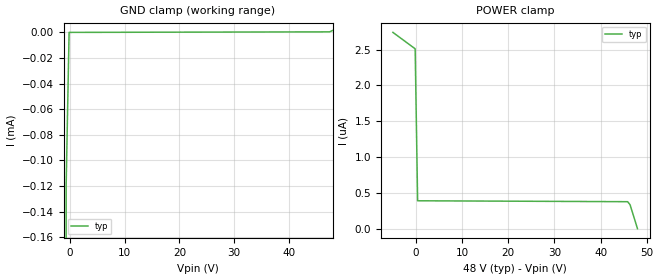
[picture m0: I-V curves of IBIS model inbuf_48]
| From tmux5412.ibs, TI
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| inbuf_48
[Model]   inbuf_48
Model_type   Input
Vinl = 0.8
Vinh = 1.3
|   typ   min   max
C_comp   1.008417e-12   NA   NA
[Voltage Range]   48   NA   NA
[Temperature Range]   27   NA   NA
[Power Clamp Reference]   48   NA   NA
[GND Clamp Reference]   0   NA   NA
[GND Clamp]
|   Voltage   I(typ)   I(min)   I(max)
-5V       -4.814A    NA         NA
-1.253V   -132.2mA   NA         NA
-717.2mV  -119.1uA   NA         NA
-181.8mV  -38.13nA   NA         NA
47.46V    388.8nA    NA         NA
48V       1.431uA    NA         NA
[POWER Clamp]
|   Voltage   I(typ)   I(min)   I(max)
-5V       2.739uA    NA         NA
-181.8mV  2.51uA     NA         NA
353.5mV   388.9nA    NA         NA
45.86V    376.1nA    NA         NA
46.39V    333.7nA    NA         NA
48V       -241.9pA   NA         NA
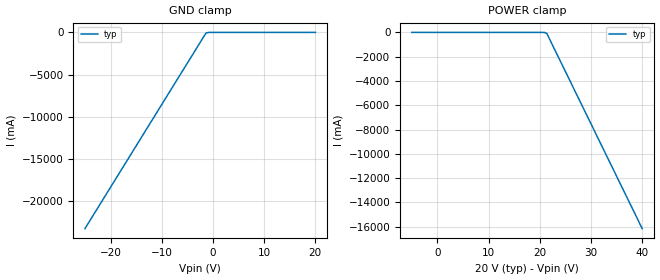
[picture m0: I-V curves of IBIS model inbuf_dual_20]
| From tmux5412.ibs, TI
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| inbuf_dual_20
[Model]   inbuf_dual_20
Model_type   Input
Vinl = 0.8
Vinh = 1.3
|   typ   min   max
C_comp   2.533030e-12   NA   NA
[Voltage Range]   20   NA   NA
[Temperature Range]   27   NA   NA
[Power Clamp Reference]   20   NA   NA
[GND Clamp Reference]   0   NA   NA
[GND Clamp]
|   Voltage   I(typ)   I(min)   I(max)
-25V      -23.23A    NA         NA
-1.364V   -80.68mA   NA         NA
-909.1mV  -7.638mA   NA         NA
-454.5mV  -770.5nA   NA         NA
20V       795.1nA    NA         NA
[POWER Clamp]
|   Voltage   I(typ)   I(min)   I(max)
-5V       1.451uA    NA         NA
20.45V    -770.5nA   NA         NA
20.91V    -7.638mA   NA         NA
21.36V    -80.68mA   NA         NA
40V       -16.16A    NA         NA
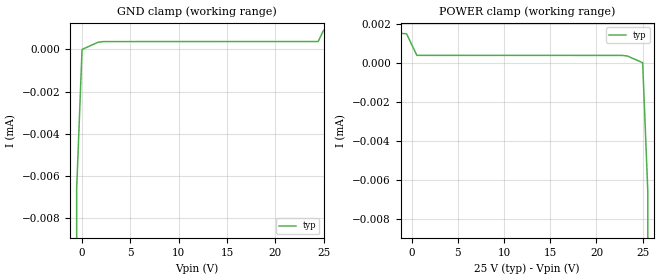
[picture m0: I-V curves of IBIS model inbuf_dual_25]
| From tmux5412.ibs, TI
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| inbuf_dual_25
[Model]   inbuf_dual_25
Model_type   Input
Vinl = 0.8
Vinh = 1.3
|   typ   min   max
C_comp   2.533030e-12   NA   NA
[Voltage Range]   25   NA   NA
[Temperature Range]   27   NA   NA
[Power Clamp Reference]   25   NA   NA
[GND Clamp Reference]   0   NA   NA
[GND Clamp]
|   Voltage   I(typ)   I(min)   I(max)
-30V      -27.84A    NA         NA
-1.111V   -37.13mA   NA         NA
-555.6mV  -6.629uA   NA         NA
0V        298pA      NA         NA
1.667V    346.5nA    NA         NA
2.222V    375.3nA    NA         NA
24.44V    377.8nA    NA         NA
25V       907.9nA    NA         NA
[POWER Clamp]
|   Voltage   I(typ)   I(min)   I(max)
-5V       1.681uA    NA         NA
-555.6mV  1.478uA    NA         NA
555.6mV   377.8nA    NA         NA
22.78V    375.3nA    NA         NA
23.33V    346.5nA    NA         NA
25V       298pA      NA         NA
25.56V    -6.629uA   NA         NA
26.11V    -37.13mA   NA         NA
50V       -20.76A    NA         NA
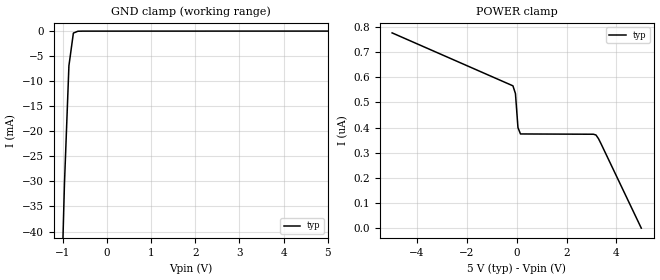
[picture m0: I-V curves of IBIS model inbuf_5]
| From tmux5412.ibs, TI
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| inbuf_5
[Model]   inbuf_5
Model_type   Input
Vinl = 0.8
Vinh = 1.3
|   typ   min   max
C_comp   2.533030e-12   NA   NA
[Voltage Range]   5   NA   NA
[Temperature Range]   27   NA   NA
[Power Clamp Reference]   5   NA   NA
[GND Clamp Reference]   0   NA   NA
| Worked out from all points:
|   GND clamp passes 1 mA (typ) near -0.77 V on its own axis
[GND Clamp]
|   Voltage   I(typ)   I(min)   I(max)
-5V       -4.814A    NA         NA
-1.061V   -63.01mA   NA         NA
-959.6mV  -30.53mA   NA         NA
-858.6mV  -6.923mA   NA         NA
-757.6mV  -397.6uA   NA         NA
-656.6mV  -30.13uA   NA         NA
-555.6mV  -6.841uA   NA         NA
5V        466.6nA    NA         NA
[POWER Clamp]
|   Voltage   I(typ)   I(min)   I(max)
-5V       776.9nA    NA         NA
-151.5mV  566.3nA    NA         NA
-50.51mV  535.5nA    NA         NA
50.51mV   399.9nA    NA         NA
151.5mV   374.8nA    NA         NA
3.081V    373.7nA    NA         NA
3.182V    370.6nA    NA         NA
3.283V    355.9nA    NA         NA
3.384V    335.9nA    NA         NA
5V        -27.16pA   NA         NA
